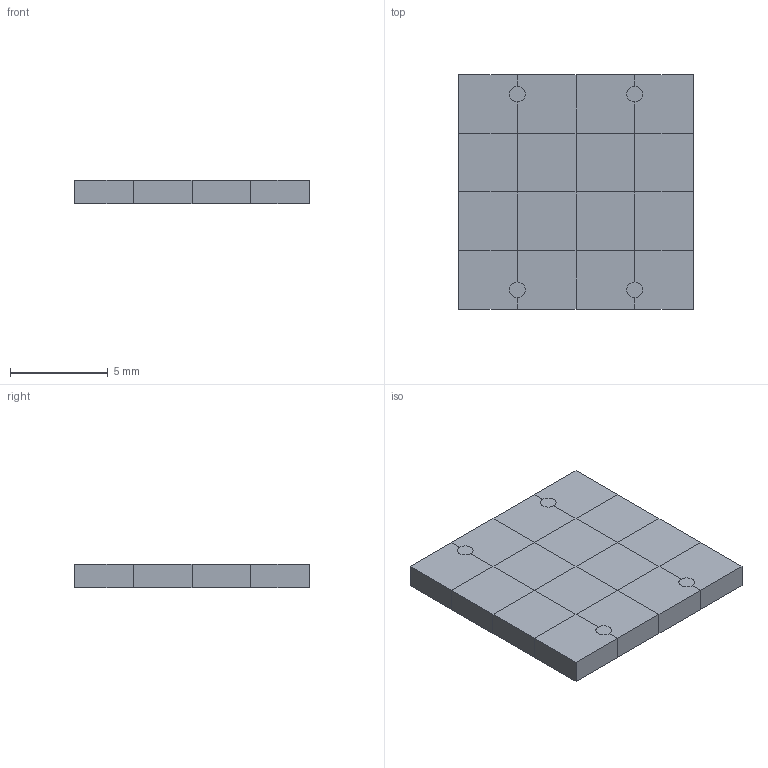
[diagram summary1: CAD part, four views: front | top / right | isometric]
STEP (ISO 10303-21) file: header records copied from the file, then geometry measured from it (millimetres).
FILE_DESCRIPTION(('Open CASCADE Model'),'2;1');
FILE_NAME('Open CASCADE Shape Model','2026-11-20T09:38:12',('Author'),( 'Open CASCADE'),'Open CASCADE STEP processor 7.9','Open CASCADE 7.9' ,'Unknown');
FILE_SCHEMA(('AUTOMOTIVE_DESIGN { 1 0 10303 214 1 1 1 1 }'));
Length unit declared in the file: millimetre
Products named in the file (3): manifold_C3; fluid; solid
Assembly tree (2 placements, depth 2):
  manifold_C3
    fluid
    solid
Bounding box: 12 x 12 x 1.2 mm (x, y, z)
Volume: 172.8 mm3; surface area: 1359.9 mm2
Topology: 2 solids, 2 shells, 1056 faces, 3696 edges, 2114 vertices
Faces by surface type: plane 1048, cylinder 8
Full cylindrical faces by diameter (mm): 0.8 x8
Entity records: 86830 total; most frequent: CARTESIAN_POINT 14309, DIRECTION 13222, LINE 11040, VECTOR 11040, ORIENTED_EDGE 7392, PCURVE 7392, DEFINITIONAL_REPRESENTATION 7392, EDGE_CURVE 3696
One B-rep face of a CAD part: STEP entity #46230.
In plain terms, the planar face has unit normal (0, 0, 1).
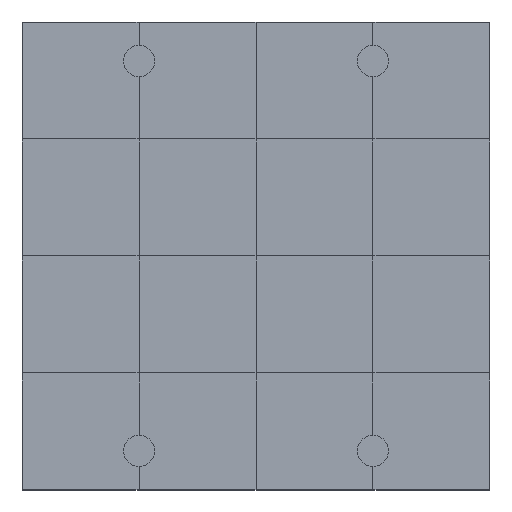
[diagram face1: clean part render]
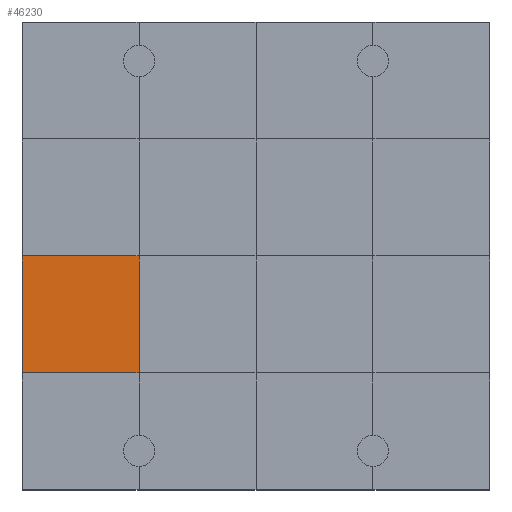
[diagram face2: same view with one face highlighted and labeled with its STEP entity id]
Its self-contained STEP definition (entity closure, numbers rounded to 3 decimals):
#45780 = VERTEX_POINT('',#45781);
#45781 = CARTESIAN_POINT('',(0.,3.,1.2));
#45795 = PLANE('',#45796);
#45796 = AXIS2_PLACEMENT_3D('',#45797,#45798,#45799);
#45797 = CARTESIAN_POINT('',(0.,3.,0.));
#45798 = DIRECTION('',(1.,0.,-0.));
#45799 = DIRECTION('',(0.,0.,1.));
#45821 = PLANE('',#45822);
#45822 = AXIS2_PLACEMENT_3D('',#45823,#45824,#45825);
#45823 = CARTESIAN_POINT('',(0.,0.,1.2));
#45824 = DIRECTION('',(0.,0.,1.));
#45825 = DIRECTION('',(1.,0.,-0.));
#45972 = VERTEX_POINT('',#45973);
#45973 = CARTESIAN_POINT('',(3.,3.,1.2));
#45994 = EDGE_CURVE('',#45780,#45972,#45995,.T.);
#45995 = SURFACE_CURVE('',#45996,(#46000,#46007),.PCURVE_S1.);
#45996 = LINE('',#45997,#45998);
#45997 = CARTESIAN_POINT('',(0.,3.,1.2));
#45998 = VECTOR('',#45999,1.);
#45999 = DIRECTION('',(1.,0.,-0.));
#46000 = PCURVE('',#45821,#46001);
#46001 = DEFINITIONAL_REPRESENTATION('',(#46002),#46006);
#46002 = LINE('',#46003,#46004);
#46003 = CARTESIAN_POINT('',(0.,3.));
#46004 = VECTOR('',#46005,1.);
#46005 = DIRECTION('',(1.,0.));
#46006 = ( GEOMETRIC_REPRESENTATION_CONTEXT(2) 
PARAMETRIC_REPRESENTATION_CONTEXT() REPRESENTATION_CONTEXT('2D SPACE',''
  ) );
#46007 = PCURVE('',#46008,#46013);
#46008 = PLANE('',#46009);
#46009 = AXIS2_PLACEMENT_3D('',#46010,#46011,#46012);
#46010 = CARTESIAN_POINT('',(0.,3.,1.2));
#46011 = DIRECTION('',(0.,0.,1.));
#46012 = DIRECTION('',(1.,0.,-0.));
#46013 = DEFINITIONAL_REPRESENTATION('',(#46014),#46018);
#46014 = LINE('',#46015,#46016);
#46015 = CARTESIAN_POINT('',(0.,0.));
#46016 = VECTOR('',#46017,1.);
#46017 = DIRECTION('',(1.,0.));
#46018 = ( GEOMETRIC_REPRESENTATION_CONTEXT(2) 
PARAMETRIC_REPRESENTATION_CONTEXT() REPRESENTATION_CONTEXT('2D SPACE',''
  ) );
#46053 = VERTEX_POINT('',#46054);
#46054 = CARTESIAN_POINT('',(0.,6.,1.2));
#46080 = EDGE_CURVE('',#45780,#46053,#46081,.T.);
#46081 = SURFACE_CURVE('',#46082,(#46086,#46093),.PCURVE_S1.);
#46082 = LINE('',#46083,#46084);
#46083 = CARTESIAN_POINT('',(0.,3.,1.2));
#46084 = VECTOR('',#46085,1.);
#46085 = DIRECTION('',(-0.,1.,0.));
#46086 = PCURVE('',#45795,#46087);
#46087 = DEFINITIONAL_REPRESENTATION('',(#46088),#46092);
#46088 = LINE('',#46089,#46090);
#46089 = CARTESIAN_POINT('',(1.2,0.));
#46090 = VECTOR('',#46091,1.);
#46091 = DIRECTION('',(0.,-1.));
#46092 = ( GEOMETRIC_REPRESENTATION_CONTEXT(2) 
PARAMETRIC_REPRESENTATION_CONTEXT() REPRESENTATION_CONTEXT('2D SPACE',''
  ) );
#46093 = PCURVE('',#46008,#46094);
#46094 = DEFINITIONAL_REPRESENTATION('',(#46095),#46099);
#46095 = LINE('',#46096,#46097);
#46096 = CARTESIAN_POINT('',(0.,0.));
#46097 = VECTOR('',#46098,1.);
#46098 = DIRECTION('',(0.,1.));
#46099 = ( GEOMETRIC_REPRESENTATION_CONTEXT(2) 
PARAMETRIC_REPRESENTATION_CONTEXT() REPRESENTATION_CONTEXT('2D SPACE',''
  ) );
#46230 = ADVANCED_FACE('',(#46231),#46008,.T.);
#46231 = FACE_BOUND('',#46232,.T.);
#46232 = EDGE_LOOP('',(#46233,#46234,#46235,#46263));
#46233 = ORIENTED_EDGE('',*,*,#46080,.F.);
#46234 = ORIENTED_EDGE('',*,*,#45994,.T.);
#46235 = ORIENTED_EDGE('',*,*,#46236,.T.);
#46236 = EDGE_CURVE('',#45972,#46237,#46239,.T.);
#46237 = VERTEX_POINT('',#46238);
#46238 = CARTESIAN_POINT('',(3.,6.,1.2));
#46239 = SURFACE_CURVE('',#46240,(#46244,#46251),.PCURVE_S1.);
#46240 = LINE('',#46241,#46242);
#46241 = CARTESIAN_POINT('',(3.,3.,1.2));
#46242 = VECTOR('',#46243,1.);
#46243 = DIRECTION('',(-0.,1.,0.));
#46244 = PCURVE('',#46008,#46245);
#46245 = DEFINITIONAL_REPRESENTATION('',(#46246),#46250);
#46246 = LINE('',#46247,#46248);
#46247 = CARTESIAN_POINT('',(3.,0.));
#46248 = VECTOR('',#46249,1.);
#46249 = DIRECTION('',(0.,1.));
#46250 = ( GEOMETRIC_REPRESENTATION_CONTEXT(2) 
PARAMETRIC_REPRESENTATION_CONTEXT() REPRESENTATION_CONTEXT('2D SPACE',''
  ) );
#46251 = PCURVE('',#46252,#46257);
#46252 = PLANE('',#46253);
#46253 = AXIS2_PLACEMENT_3D('',#46254,#46255,#46256);
#46254 = CARTESIAN_POINT('',(3.,3.,1.2));
#46255 = DIRECTION('',(0.,0.,1.));
#46256 = DIRECTION('',(1.,0.,-0.));
#46257 = DEFINITIONAL_REPRESENTATION('',(#46258),#46262);
#46258 = LINE('',#46259,#46260);
#46259 = CARTESIAN_POINT('',(0.,0.));
#46260 = VECTOR('',#46261,1.);
#46261 = DIRECTION('',(0.,1.));
#46262 = ( GEOMETRIC_REPRESENTATION_CONTEXT(2) 
PARAMETRIC_REPRESENTATION_CONTEXT() REPRESENTATION_CONTEXT('2D SPACE',''
  ) );
#46263 = ORIENTED_EDGE('',*,*,#46264,.F.);
#46264 = EDGE_CURVE('',#46053,#46237,#46265,.T.);
#46265 = SURFACE_CURVE('',#46266,(#46270,#46277),.PCURVE_S1.);
#46266 = LINE('',#46267,#46268);
#46267 = CARTESIAN_POINT('',(0.,6.,1.2));
#46268 = VECTOR('',#46269,1.);
#46269 = DIRECTION('',(1.,0.,-0.));
#46270 = PCURVE('',#46008,#46271);
#46271 = DEFINITIONAL_REPRESENTATION('',(#46272),#46276);
#46272 = LINE('',#46273,#46274);
#46273 = CARTESIAN_POINT('',(0.,3.));
#46274 = VECTOR('',#46275,1.);
#46275 = DIRECTION('',(1.,0.));
#46276 = ( GEOMETRIC_REPRESENTATION_CONTEXT(2) 
PARAMETRIC_REPRESENTATION_CONTEXT() REPRESENTATION_CONTEXT('2D SPACE',''
  ) );
#46277 = PCURVE('',#46278,#46283);
#46278 = PLANE('',#46279);
#46279 = AXIS2_PLACEMENT_3D('',#46280,#46281,#46282);
#46280 = CARTESIAN_POINT('',(0.,6.,1.2));
#46281 = DIRECTION('',(0.,0.,1.));
#46282 = DIRECTION('',(1.,0.,-0.));
#46283 = DEFINITIONAL_REPRESENTATION('',(#46284),#46288);
#46284 = LINE('',#46285,#46286);
#46285 = CARTESIAN_POINT('',(0.,0.));
#46286 = VECTOR('',#46287,1.);
#46287 = DIRECTION('',(1.,0.));
#46288 = ( GEOMETRIC_REPRESENTATION_CONTEXT(2) 
PARAMETRIC_REPRESENTATION_CONTEXT() REPRESENTATION_CONTEXT('2D SPACE',''
  ) );
